VERSION 5.7 ;
  NOWIREEXTENSIONATPIN ON ;
  DIVIDERCHAR "/" ;
  BUSBITCHARS "[]" ;
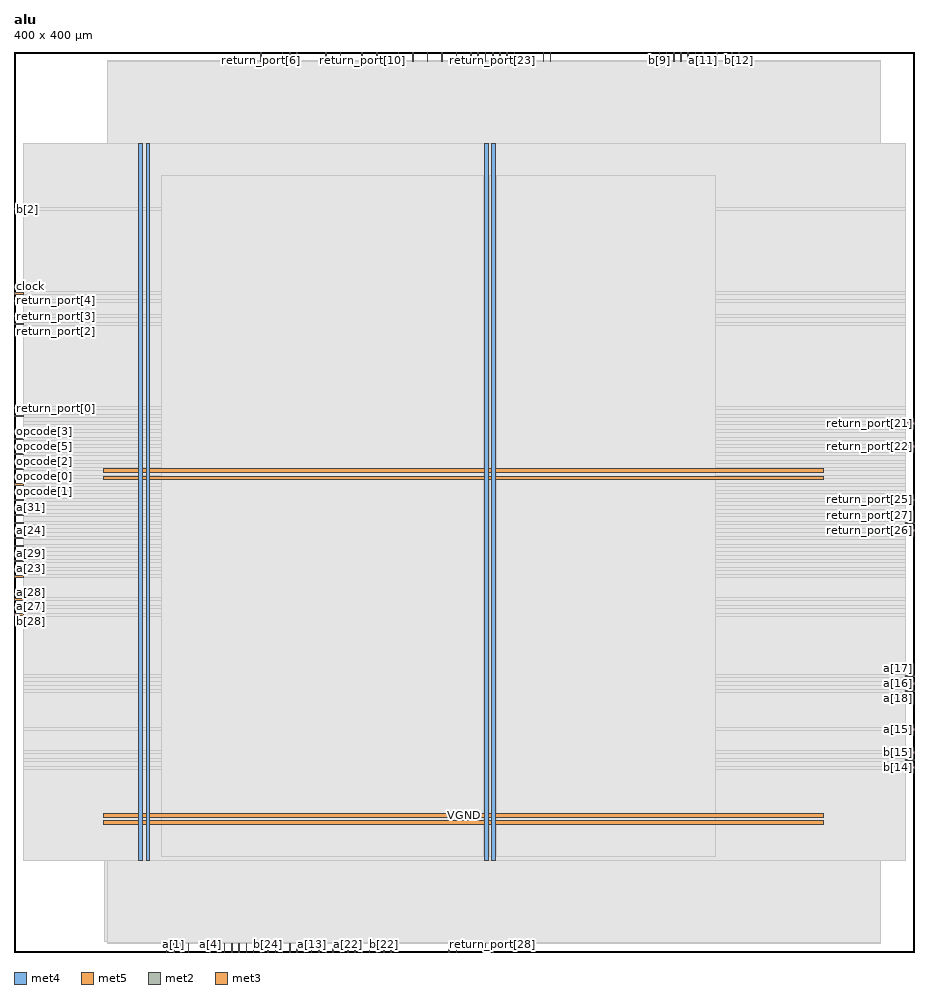
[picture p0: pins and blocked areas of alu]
MACRO alu
  CLASS BLOCK ;
  FOREIGN alu ;
  ORIGIN 0.000 0.000 ;
  SIZE 400.000 BY 400.000 ;
  PIN VGND
    DIRECTION INOUT ;
    USE GROUND ;
    PORT
      LAYER met4 ;
        RECT 58.840 40.560 60.440 359.280 ;
    END
    PORT
      LAYER met4 ;
        RECT 212.440 40.560 214.040 359.280 ;
    END
    PORT
      LAYER met5 ;
        RECT 39.780 59.950 359.960 61.550 ;
    END
    PORT
      LAYER met5 ;
        RECT 39.780 213.130 359.960 214.730 ;
    END
  END VGND
  PIN VPWR
    DIRECTION INOUT ;
    USE POWER ;
    PORT
      LAYER met4 ;
        RECT 55.540 40.560 57.140 359.280 ;
    END
    PORT
      LAYER met4 ;
        RECT 209.140 40.560 210.740 359.280 ;
    END
    PORT
      LAYER met5 ;
        RECT 39.780 56.650 359.960 58.250 ;
    END
    PORT
      LAYER met5 ;
        RECT 39.780 209.830 359.960 211.430 ;
    END
  END VPWR
  PIN a[0]
    DIRECTION INPUT ;
    USE SIGNAL ;
    ANTENNAGATEAREA 0.213000 ;
    PORT
      LAYER met2 ;
        RECT 67.710 0.000 67.990 4.000 ;
    END
  END a[0]
  PIN a[10]
    DIRECTION INPUT ;
    USE SIGNAL ;
    ANTENNAGATEAREA 0.213000 ;
    PORT
      LAYER met2 ;
        RECT 119.230 0.000 119.510 4.000 ;
    END
  END a[10]
  PIN a[11]
    DIRECTION INPUT ;
    USE SIGNAL ;
    ANTENNAGATEAREA 0.213000 ;
    PORT
      LAYER met2 ;
        RECT 305.990 396.000 306.270 400.000 ;
    END
  END a[11]
  PIN a[12]
    DIRECTION INPUT ;
    USE SIGNAL ;
    ANTENNAGATEAREA 0.159000 ;
    PORT
      LAYER met2 ;
        RECT 128.890 0.000 129.170 4.000 ;
    END
  END a[12]
  PIN a[13]
    DIRECTION INPUT ;
    USE SIGNAL ;
    ANTENNAGATEAREA 0.159000 ;
    PORT
      LAYER met2 ;
        RECT 132.110 0.000 132.390 4.000 ;
    END
  END a[13]
  PIN a[14]
    DIRECTION INPUT ;
    USE SIGNAL ;
    ANTENNAGATEAREA 0.213000 ;
    PORT
      LAYER met2 ;
        RECT 135.330 0.000 135.610 4.000 ;
    END
  END a[14]
  PIN a[15]
    DIRECTION INPUT ;
    USE SIGNAL ;
    ANTENNAGATEAREA 0.196500 ;
    PORT
      LAYER met3 ;
        RECT 396.000 98.640 400.000 99.240 ;
    END
  END a[15]
  PIN a[16]
    DIRECTION INPUT ;
    USE SIGNAL ;
    ANTENNAGATEAREA 0.196500 ;
    PORT
      LAYER met3 ;
        RECT 396.000 119.040 400.000 119.640 ;
    END
  END a[16]
  PIN a[17]
    DIRECTION INPUT ;
    USE SIGNAL ;
    ANTENNAGATEAREA 0.196500 ;
    PORT
      LAYER met3 ;
        RECT 396.000 122.440 400.000 123.040 ;
    END
  END a[17]
  PIN a[18]
    DIRECTION INPUT ;
    USE SIGNAL ;
    ANTENNAGATEAREA 0.196500 ;
    PORT
      LAYER met3 ;
        RECT 396.000 115.640 400.000 116.240 ;
    END
  END a[18]
  PIN a[19]
    DIRECTION INPUT ;
    USE SIGNAL ;
    ANTENNAGATEAREA 0.213000 ;
    PORT
      LAYER met2 ;
        RECT 141.770 0.000 142.050 4.000 ;
    END
  END a[19]
  PIN a[1]
    DIRECTION INPUT ;
    USE SIGNAL ;
    ANTENNAGATEAREA 0.196500 ;
    PORT
      LAYER met2 ;
        RECT 70.930 0.000 71.210 4.000 ;
    END
  END a[1]
  PIN a[20]
    DIRECTION INPUT ;
    USE SIGNAL ;
    ANTENNAGATEAREA 0.213000 ;
    PORT
      LAYER met2 ;
        RECT 138.550 0.000 138.830 4.000 ;
    END
  END a[20]
  PIN a[21]
    DIRECTION INPUT ;
    USE SIGNAL ;
    ANTENNAGATEAREA 0.196500 ;
    PORT
      LAYER met2 ;
        RECT 144.990 0.000 145.270 4.000 ;
    END
  END a[21]
  PIN a[22]
    DIRECTION INPUT ;
    USE SIGNAL ;
    ANTENNAGATEAREA 0.196500 ;
    PORT
      LAYER met2 ;
        RECT 148.210 0.000 148.490 4.000 ;
    END
  END a[22]
  PIN a[23]
    DIRECTION INPUT ;
    USE SIGNAL ;
    ANTENNAGATEAREA 0.213000 ;
    PORT
      LAYER met3 ;
        RECT 0.000 170.040 4.000 170.640 ;
    END
  END a[23]
  PIN a[24]
    DIRECTION INPUT ;
    USE SIGNAL ;
    ANTENNAGATEAREA 0.631200 ;
    ANTENNADIFFAREA 0.434700 ;
    PORT
      LAYER met3 ;
        RECT 0.000 187.040 4.000 187.640 ;
    END
  END a[24]
  PIN a[25]
    DIRECTION INPUT ;
    USE SIGNAL ;
    ANTENNAGATEAREA 0.196500 ;
    PORT
      LAYER met2 ;
        RECT 106.350 0.000 106.630 4.000 ;
    END
  END a[25]
  PIN a[26]
    DIRECTION INPUT ;
    USE SIGNAL ;
    ANTENNAGATEAREA 0.213000 ;
    PORT
      LAYER met3 ;
        RECT 0.000 166.640 4.000 167.240 ;
    END
  END a[26]
  PIN a[27]
    DIRECTION INPUT ;
    USE SIGNAL ;
    ANTENNAGATEAREA 0.560700 ;
    ANTENNADIFFAREA 0.434700 ;
    PORT
      LAYER met3 ;
        RECT 0.000 153.040 4.000 153.640 ;
    END
  END a[27]
  PIN a[28]
    DIRECTION INPUT ;
    USE SIGNAL ;
    ANTENNAGATEAREA 0.213000 ;
    PORT
      LAYER met3 ;
        RECT 0.000 156.440 4.000 157.040 ;
    END
  END a[28]
  PIN a[29]
    DIRECTION INPUT ;
    USE SIGNAL ;
    ANTENNAGATEAREA 0.593700 ;
    ANTENNADIFFAREA 0.434700 ;
    PORT
      LAYER met3 ;
        RECT 0.000 176.840 4.000 177.440 ;
    END
  END a[29]
  PIN a[2]
    DIRECTION INPUT ;
    USE SIGNAL ;
    ANTENNAGATEAREA 0.213000 ;
    PORT
      LAYER met2 ;
        RECT 74.150 0.000 74.430 4.000 ;
    END
  END a[2]
  PIN a[30]
    DIRECTION INPUT ;
    USE SIGNAL ;
    ANTENNAGATEAREA 0.247500 ;
    PORT
      LAYER met3 ;
        RECT 0.000 180.240 4.000 180.840 ;
    END
  END a[30]
  PIN a[31]
    DIRECTION INPUT ;
    USE SIGNAL ;
    ANTENNAGATEAREA 0.560700 ;
    ANTENNADIFFAREA 0.434700 ;
    PORT
      LAYER met3 ;
        RECT 0.000 197.240 4.000 197.840 ;
    END
  END a[31]
  PIN a[3]
    DIRECTION INPUT ;
    USE SIGNAL ;
    ANTENNAGATEAREA 0.247500 ;
    PORT
      LAYER met2 ;
        RECT 77.370 0.000 77.650 4.000 ;
    END
  END a[3]
  PIN a[4]
    DIRECTION INPUT ;
    USE SIGNAL ;
    ANTENNAGATEAREA 0.213000 ;
    PORT
      LAYER met2 ;
        RECT 87.030 0.000 87.310 4.000 ;
    END
  END a[4]
  PIN a[5]
    DIRECTION INPUT ;
    USE SIGNAL ;
    ANTENNAGATEAREA 0.213000 ;
    PORT
      LAYER met2 ;
        RECT 90.250 0.000 90.530 4.000 ;
    END
  END a[5]
  PIN a[6]
    DIRECTION INPUT ;
    USE SIGNAL ;
    ANTENNAGATEAREA 0.213000 ;
    PORT
      LAYER met2 ;
        RECT 93.470 0.000 93.750 4.000 ;
    END
  END a[6]
  PIN a[7]
    DIRECTION INPUT ;
    USE SIGNAL ;
    ANTENNAGATEAREA 0.196500 ;
    PORT
      LAYER met2 ;
        RECT 109.570 0.000 109.850 4.000 ;
    END
  END a[7]
  PIN a[8]
    DIRECTION INPUT ;
    USE SIGNAL ;
    ANTENNAGATEAREA 0.213000 ;
    PORT
      LAYER met2 ;
        RECT 116.010 0.000 116.290 4.000 ;
    END
  END a[8]
  PIN a[9]
    DIRECTION INPUT ;
    USE SIGNAL ;
    ANTENNAGATEAREA 0.196500 ;
    PORT
      LAYER met2 ;
        RECT 122.450 0.000 122.730 4.000 ;
    END
  END a[9]
  PIN b[0]
    DIRECTION INPUT ;
    USE SIGNAL ;
    ANTENNAGATEAREA 0.196500 ;
    PORT
      LAYER met2 ;
        RECT 238.370 396.000 238.650 400.000 ;
    END
  END b[0]
  PIN b[10]
    DIRECTION INPUT ;
    USE SIGNAL ;
    ANTENNAGATEAREA 0.126000 ;
    PORT
      LAYER met2 ;
        RECT 302.770 396.000 303.050 400.000 ;
    END
  END b[10]
  PIN b[11]
    DIRECTION INPUT ;
    USE SIGNAL ;
    ANTENNAGATEAREA 0.196500 ;
    PORT
      LAYER met2 ;
        RECT 312.430 396.000 312.710 400.000 ;
    END
  END b[11]
  PIN b[12]
    DIRECTION INPUT ;
    USE SIGNAL ;
    ANTENNAGATEAREA 0.213000 ;
    PORT
      LAYER met2 ;
        RECT 322.090 396.000 322.370 400.000 ;
    END
  END b[12]
  PIN b[13]
    DIRECTION INPUT ;
    USE SIGNAL ;
    ANTENNAGATEAREA 0.196500 ;
    PORT
      LAYER met2 ;
        RECT 318.870 396.000 319.150 400.000 ;
    END
  END b[13]
  PIN b[14]
    DIRECTION INPUT ;
    USE SIGNAL ;
    ANTENNAGATEAREA 0.196500 ;
    PORT
      LAYER met3 ;
        RECT 396.000 81.640 400.000 82.240 ;
    END
  END b[14]
  PIN b[15]
    DIRECTION INPUT ;
    USE SIGNAL ;
    ANTENNAGATEAREA 0.196500 ;
    PORT
      LAYER met3 ;
        RECT 396.000 85.040 400.000 85.640 ;
    END
  END b[15]
  PIN b[16]
    DIRECTION INPUT ;
    USE SIGNAL ;
    ANTENNAGATEAREA 0.213000 ;
    PORT
      LAYER met3 ;
        RECT 396.000 88.440 400.000 89.040 ;
    END
  END b[16]
  PIN b[17]
    DIRECTION INPUT ;
    USE SIGNAL ;
    ANTENNAGATEAREA 0.196500 ;
    PORT
      LAYER met2 ;
        RECT 151.430 0.000 151.710 4.000 ;
    END
  END b[17]
  PIN b[18]
    DIRECTION INPUT ;
    USE SIGNAL ;
    ANTENNAGATEAREA 0.159000 ;
    PORT
      LAYER met2 ;
        RECT 154.650 0.000 154.930 4.000 ;
    END
  END b[18]
  PIN b[19]
    DIRECTION INPUT ;
    USE SIGNAL ;
    ANTENNAGATEAREA 0.196500 ;
    PORT
      LAYER met2 ;
        RECT 157.870 0.000 158.150 4.000 ;
    END
  END b[19]
  PIN b[1]
    DIRECTION INPUT ;
    USE SIGNAL ;
    ANTENNAGATEAREA 0.159000 ;
    PORT
      LAYER met2 ;
        RECT 235.150 396.000 235.430 400.000 ;
    END
  END b[1]
  PIN b[20]
    DIRECTION INPUT ;
    USE SIGNAL ;
    ANTENNAGATEAREA 0.196500 ;
    PORT
      LAYER met2 ;
        RECT 125.670 0.000 125.950 4.000 ;
    END
  END b[20]
  PIN b[21]
    DIRECTION INPUT ;
    USE SIGNAL ;
    ANTENNAGATEAREA 0.196500 ;
    PORT
      LAYER met2 ;
        RECT 161.090 0.000 161.370 4.000 ;
    END
  END b[21]
  PIN b[22]
    DIRECTION INPUT ;
    USE SIGNAL ;
    ANTENNAGATEAREA 0.196500 ;
    PORT
      LAYER met2 ;
        RECT 164.310 0.000 164.590 4.000 ;
    END
  END b[22]
  PIN b[23]
    DIRECTION INPUT ;
    USE SIGNAL ;
    ANTENNAGATEAREA 0.196500 ;
    PORT
      LAYER met2 ;
        RECT 103.130 0.000 103.410 4.000 ;
    END
  END b[23]
  PIN b[24]
    DIRECTION INPUT ;
    USE SIGNAL ;
    ANTENNAGATEAREA 0.196500 ;
    PORT
      LAYER met2 ;
        RECT 112.790 0.000 113.070 4.000 ;
    END
  END b[24]
  PIN b[25]
    DIRECTION INPUT ;
    USE SIGNAL ;
    ANTENNAGATEAREA 0.196500 ;
    PORT
      LAYER met2 ;
        RECT 167.530 0.000 167.810 4.000 ;
    END
  END b[25]
  PIN b[26]
    DIRECTION INPUT ;
    USE SIGNAL ;
    ANTENNAGATEAREA 0.196500 ;
    PORT
      LAYER met2 ;
        RECT 96.690 0.000 96.970 4.000 ;
    END
  END b[26]
  PIN b[27]
    DIRECTION INPUT ;
    USE SIGNAL ;
    ANTENNAGATEAREA 0.213000 ;
    PORT
      LAYER met2 ;
        RECT 99.910 0.000 100.190 4.000 ;
    END
  END b[27]
  PIN b[28]
    DIRECTION INPUT ;
    USE SIGNAL ;
    ANTENNAGATEAREA 0.213000 ;
    PORT
      LAYER met3 ;
        RECT 0.000 149.640 4.000 150.240 ;
    END
  END b[28]
  PIN b[29]
    DIRECTION INPUT ;
    USE SIGNAL ;
    ANTENNAGATEAREA 0.593700 ;
    ANTENNADIFFAREA 0.434700 ;
    PORT
      LAYER met3 ;
        RECT 0.000 173.440 4.000 174.040 ;
    END
  END b[29]
  PIN b[2]
    DIRECTION INPUT ;
    USE SIGNAL ;
    ANTENNAGATEAREA 0.213000 ;
    PORT
      LAYER met3 ;
        RECT 0.000 329.840 4.000 330.440 ;
    END
  END b[2]
  PIN b[30]
    DIRECTION INPUT ;
    USE SIGNAL ;
    ANTENNAGATEAREA 0.213000 ;
    PORT
      LAYER met3 ;
        RECT 0.000 183.640 4.000 184.240 ;
    END
  END b[30]
  PIN b[31]
    DIRECTION INPUT ;
    USE SIGNAL ;
    ANTENNAGATEAREA 0.631200 ;
    ANTENNADIFFAREA 0.434700 ;
    PORT
      LAYER met3 ;
        RECT 0.000 190.440 4.000 191.040 ;
    END
  END b[31]
  PIN b[3]
    DIRECTION INPUT ;
    USE SIGNAL ;
    ANTENNAGATEAREA 0.196500 ;
    PORT
      LAYER met2 ;
        RECT 222.270 396.000 222.550 400.000 ;
    END
  END b[3]
  PIN b[4]
    DIRECTION INPUT ;
    USE SIGNAL ;
    ANTENNAGATEAREA 0.196500 ;
    PORT
      LAYER met2 ;
        RECT 219.050 396.000 219.330 400.000 ;
    END
  END b[4]
  PIN b[5]
    DIRECTION INPUT ;
    USE SIGNAL ;
    ANTENNAGATEAREA 0.213000 ;
    PORT
      LAYER met2 ;
        RECT 299.550 396.000 299.830 400.000 ;
    END
  END b[5]
  PIN b[6]
    DIRECTION INPUT ;
    USE SIGNAL ;
    ANTENNAGATEAREA 0.159000 ;
    PORT
      LAYER met2 ;
        RECT 296.330 396.000 296.610 400.000 ;
    END
  END b[6]
  PIN b[7]
    DIRECTION INPUT ;
    USE SIGNAL ;
    ANTENNAGATEAREA 0.213000 ;
    PORT
      LAYER met2 ;
        RECT 293.110 396.000 293.390 400.000 ;
    END
  END b[7]
  PIN b[8]
    DIRECTION INPUT ;
    USE SIGNAL ;
    ANTENNAGATEAREA 0.196500 ;
    PORT
      LAYER met2 ;
        RECT 289.890 396.000 290.170 400.000 ;
    END
  END b[8]
  PIN b[9]
    DIRECTION INPUT ;
    USE SIGNAL ;
    ANTENNAGATEAREA 0.126000 ;
    PORT
      LAYER met2 ;
        RECT 286.670 396.000 286.950 400.000 ;
    END
  END b[9]
  PIN clock
    DIRECTION INPUT ;
    USE SIGNAL ;
    ANTENNAGATEAREA 0.196500 ;
    PORT
      LAYER met3 ;
        RECT 0.000 292.440 4.000 293.040 ;
    END
  END clock
  PIN done_port
    DIRECTION OUTPUT ;
    USE SIGNAL ;
    ANTENNADIFFAREA 0.795200 ;
    PORT
      LAYER met3 ;
        RECT 0.000 193.840 4.000 194.440 ;
    END
  END done_port
  PIN opcode[0]
    DIRECTION INPUT ;
    USE SIGNAL ;
    ANTENNAGATEAREA 0.196500 ;
    PORT
      LAYER met3 ;
        RECT 0.000 210.840 4.000 211.440 ;
    END
  END opcode[0]
  PIN opcode[1]
    DIRECTION INPUT ;
    USE SIGNAL ;
    ANTENNAGATEAREA 0.213000 ;
    PORT
      LAYER met3 ;
        RECT 0.000 207.440 4.000 208.040 ;
    END
  END opcode[1]
  PIN opcode[2]
    DIRECTION INPUT ;
    USE SIGNAL ;
    ANTENNAGATEAREA 0.631200 ;
    ANTENNADIFFAREA 0.434700 ;
    PORT
      LAYER met3 ;
        RECT 0.000 214.240 4.000 214.840 ;
    END
  END opcode[2]
  PIN opcode[3]
    DIRECTION INPUT ;
    USE SIGNAL ;
    ANTENNAGATEAREA 0.196500 ;
    PORT
      LAYER met3 ;
        RECT 0.000 231.240 4.000 231.840 ;
    END
  END opcode[3]
  PIN opcode[4]
    DIRECTION INPUT ;
    USE SIGNAL ;
    ANTENNAGATEAREA 0.196500 ;
    PORT
      LAYER met3 ;
        RECT 0.000 217.640 4.000 218.240 ;
    END
  END opcode[4]
  PIN opcode[5]
    DIRECTION INPUT ;
    USE SIGNAL ;
    ANTENNAGATEAREA 0.196500 ;
    PORT
      LAYER met3 ;
        RECT 0.000 224.440 4.000 225.040 ;
    END
  END opcode[5]
  PIN opcode[6]
    DIRECTION INPUT ;
    USE SIGNAL ;
    ANTENNAGATEAREA 0.631200 ;
    ANTENNADIFFAREA 0.434700 ;
    PORT
      LAYER met3 ;
        RECT 0.000 227.840 4.000 228.440 ;
    END
  END opcode[6]
  PIN opcode[7]
    DIRECTION INPUT ;
    USE SIGNAL ;
    ANTENNAGATEAREA 0.631200 ;
    ANTENNADIFFAREA 0.434700 ;
    PORT
      LAYER met3 ;
        RECT 0.000 221.040 4.000 221.640 ;
    END
  END opcode[7]
  PIN reset
    DIRECTION INPUT ;
    USE SIGNAL ;
    ANTENNAGATEAREA 0.631200 ;
    ANTENNADIFFAREA 0.434700 ;
    PORT
      LAYER met3 ;
        RECT 0.000 204.040 4.000 204.640 ;
    END
  END reset
  PIN return_port[0]
    DIRECTION OUTPUT ;
    USE SIGNAL ;
    ANTENNADIFFAREA 0.795200 ;
    PORT
      LAYER met3 ;
        RECT 0.000 241.440 4.000 242.040 ;
    END
  END return_port[0]
  PIN return_port[10]
    DIRECTION OUTPUT ;
    USE SIGNAL ;
    ANTENNADIFFAREA 0.795200 ;
    PORT
      LAYER met2 ;
        RECT 154.650 396.000 154.930 400.000 ;
    END
  END return_port[10]
  PIN return_port[11]
    DIRECTION OUTPUT ;
    USE SIGNAL ;
    ANTENNADIFFAREA 0.795200 ;
    PORT
      LAYER met2 ;
        RECT 138.550 396.000 138.830 400.000 ;
    END
  END return_port[11]
  PIN return_port[12]
    DIRECTION OUTPUT ;
    USE SIGNAL ;
    ANTENNADIFFAREA 0.795200 ;
    PORT
      LAYER met2 ;
        RECT 170.750 396.000 171.030 400.000 ;
    END
  END return_port[12]
  PIN return_port[13]
    DIRECTION OUTPUT ;
    USE SIGNAL ;
    ANTENNADIFFAREA 0.795200 ;
    PORT
      LAYER met2 ;
        RECT 161.090 396.000 161.370 400.000 ;
    END
  END return_port[13]
  PIN return_port[14]
    DIRECTION OUTPUT ;
    USE SIGNAL ;
    ANTENNADIFFAREA 0.795200 ;
    PORT
      LAYER met2 ;
        RECT 183.630 396.000 183.910 400.000 ;
    END
  END return_port[14]
  PIN return_port[15]
    DIRECTION OUTPUT ;
    USE SIGNAL ;
    ANTENNADIFFAREA 0.795200 ;
    PORT
      LAYER met2 ;
        RECT 177.190 396.000 177.470 400.000 ;
    END
  END return_port[15]
  PIN return_port[16]
    DIRECTION OUTPUT ;
    USE SIGNAL ;
    ANTENNADIFFAREA 0.795200 ;
    PORT
      LAYER met2 ;
        RECT 196.510 396.000 196.790 400.000 ;
    END
  END return_port[16]
  PIN return_port[17]
    DIRECTION OUTPUT ;
    USE SIGNAL ;
    ANTENNADIFFAREA 0.795200 ;
    PORT
      LAYER met2 ;
        RECT 190.070 396.000 190.350 400.000 ;
    END
  END return_port[17]
  PIN return_port[18]
    DIRECTION OUTPUT ;
    USE SIGNAL ;
    ANTENNADIFFAREA 0.795200 ;
    PORT
      LAYER met2 ;
        RECT 202.950 396.000 203.230 400.000 ;
    END
  END return_port[18]
  PIN return_port[19]
    DIRECTION OUTPUT ;
    USE SIGNAL ;
    ANTENNADIFFAREA 0.795200 ;
    PORT
      LAYER met2 ;
        RECT 215.830 396.000 216.110 400.000 ;
    END
  END return_port[19]
  PIN return_port[1]
    DIRECTION OUTPUT ;
    USE SIGNAL ;
    ANTENNADIFFAREA 0.795200 ;
    PORT
      LAYER met3 ;
        RECT 0.000 238.040 4.000 238.640 ;
    END
  END return_port[1]
  PIN return_port[20]
    DIRECTION OUTPUT ;
    USE SIGNAL ;
    ANTENNADIFFAREA 0.795200 ;
    PORT
      LAYER met2 ;
        RECT 206.170 396.000 206.450 400.000 ;
    END
  END return_port[20]
  PIN return_port[21]
    DIRECTION OUTPUT ;
    USE SIGNAL ;
    ANTENNADIFFAREA 0.795200 ;
    PORT
      LAYER met3 ;
        RECT 396.000 234.640 400.000 235.240 ;
    END
  END return_port[21]
  PIN return_port[22]
    DIRECTION OUTPUT ;
    USE SIGNAL ;
    ANTENNADIFFAREA 0.795200 ;
    PORT
      LAYER met3 ;
        RECT 396.000 224.440 400.000 225.040 ;
    END
  END return_port[22]
  PIN return_port[23]
    DIRECTION OUTPUT ;
    USE SIGNAL ;
    ANTENNADIFFAREA 0.795200 ;
    PORT
      LAYER met2 ;
        RECT 212.610 396.000 212.890 400.000 ;
    END
  END return_port[23]
  PIN return_port[24]
    DIRECTION OUTPUT ;
    USE SIGNAL ;
    ANTENNADIFFAREA 0.795200 ;
    PORT
      LAYER met2 ;
        RECT 209.390 396.000 209.670 400.000 ;
    END
  END return_port[24]
  PIN return_port[25]
    DIRECTION OUTPUT ;
    USE SIGNAL ;
    ANTENNADIFFAREA 0.795200 ;
    PORT
      LAYER met3 ;
        RECT 396.000 200.640 400.000 201.240 ;
    END
  END return_port[25]
  PIN return_port[26]
    DIRECTION OUTPUT ;
    USE SIGNAL ;
    ANTENNADIFFAREA 0.795200 ;
    PORT
      LAYER met3 ;
        RECT 396.000 187.040 400.000 187.640 ;
    END
  END return_port[26]
  PIN return_port[27]
    DIRECTION OUTPUT ;
    USE SIGNAL ;
    ANTENNADIFFAREA 0.795200 ;
    PORT
      LAYER met3 ;
        RECT 396.000 190.440 400.000 191.040 ;
    END
  END return_port[27]
  PIN return_port[28]
    DIRECTION OUTPUT ;
    USE SIGNAL ;
    ANTENNADIFFAREA 0.795200 ;
    PORT
      LAYER met2 ;
        RECT 212.610 0.000 212.890 4.000 ;
    END
  END return_port[28]
  PIN return_port[29]
    DIRECTION OUTPUT ;
    USE SIGNAL ;
    ANTENNADIFFAREA 0.795200 ;
    PORT
      LAYER met2 ;
        RECT 209.390 0.000 209.670 4.000 ;
    END
  END return_port[29]
  PIN return_port[2]
    DIRECTION OUTPUT ;
    USE SIGNAL ;
    ANTENNADIFFAREA 0.795200 ;
    PORT
      LAYER met3 ;
        RECT 0.000 278.840 4.000 279.440 ;
    END
  END return_port[2]
  PIN return_port[30]
    DIRECTION OUTPUT ;
    USE SIGNAL ;
    ANTENNADIFFAREA 0.795200 ;
    PORT
      LAYER met2 ;
        RECT 196.510 0.000 196.790 4.000 ;
    END
  END return_port[30]
  PIN return_port[31]
    DIRECTION OUTPUT ;
    USE SIGNAL ;
    ANTENNADIFFAREA 0.795200 ;
    PORT
      LAYER met2 ;
        RECT 193.290 0.000 193.570 4.000 ;
    END
  END return_port[31]
  PIN return_port[3]
    DIRECTION OUTPUT ;
    USE SIGNAL ;
    ANTENNADIFFAREA 0.795200 ;
    PORT
      LAYER met3 ;
        RECT 0.000 282.240 4.000 282.840 ;
    END
  END return_port[3]
  PIN return_port[4]
    DIRECTION OUTPUT ;
    USE SIGNAL ;
    ANTENNADIFFAREA 0.795200 ;
    PORT
      LAYER met3 ;
        RECT 0.000 289.040 4.000 289.640 ;
    END
  END return_port[4]
  PIN return_port[5]
    DIRECTION OUTPUT ;
    USE SIGNAL ;
    ANTENNADIFFAREA 0.795200 ;
    PORT
      LAYER met2 ;
        RECT 122.450 396.000 122.730 400.000 ;
    END
  END return_port[5]
  PIN return_port[6]
    DIRECTION OUTPUT ;
    USE SIGNAL ;
    ANTENNADIFFAREA 0.795200 ;
    PORT
      LAYER met2 ;
        RECT 109.570 396.000 109.850 400.000 ;
    END
  END return_port[6]
  PIN return_port[7]
    DIRECTION OUTPUT ;
    USE SIGNAL ;
    ANTENNADIFFAREA 0.795200 ;
    PORT
      LAYER met2 ;
        RECT 119.230 396.000 119.510 400.000 ;
    END
  END return_port[7]
  PIN return_port[8]
    DIRECTION OUTPUT ;
    USE SIGNAL ;
    ANTENNADIFFAREA 0.795200 ;
    PORT
      LAYER met2 ;
        RECT 125.670 396.000 125.950 400.000 ;
    END
  END return_port[8]
  PIN return_port[9]
    DIRECTION OUTPUT ;
    USE SIGNAL ;
    ANTENNADIFFAREA 0.795200 ;
    PORT
      LAYER met2 ;
        RECT 144.990 396.000 145.270 400.000 ;
    END
  END return_port[9]
  PIN start_port
    DIRECTION INPUT ;
    USE SIGNAL ;
    ANTENNAGATEAREA 0.631200 ;
    ANTENNADIFFAREA 0.434700 ;
    PORT
      LAYER met3 ;
        RECT 0.000 200.640 4.000 201.240 ;
    END
  END start_port
  OBS
      LAYER nwell ;
        RECT 39.830 40.715 359.910 359.230 ;
      LAYER li1 ;
        RECT 40.020 40.715 359.720 359.125 ;
      LAYER met1 ;
        RECT 40.020 4.800 384.950 359.280 ;
      LAYER met2 ;
        RECT 41.490 395.720 109.290 396.170 ;
        RECT 110.130 395.720 118.950 396.170 ;
        RECT 119.790 395.720 122.170 396.170 ;
        RECT 123.010 395.720 125.390 396.170 ;
        RECT 126.230 395.720 138.270 396.170 ;
        RECT 139.110 395.720 144.710 396.170 ;
        RECT 145.550 395.720 154.370 396.170 ;
        RECT 155.210 395.720 160.810 396.170 ;
        RECT 161.650 395.720 170.470 396.170 ;
        RECT 171.310 395.720 176.910 396.170 ;
        RECT 177.750 395.720 183.350 396.170 ;
        RECT 184.190 395.720 189.790 396.170 ;
        RECT 190.630 395.720 196.230 396.170 ;
        RECT 197.070 395.720 202.670 396.170 ;
        RECT 203.510 395.720 205.890 396.170 ;
        RECT 206.730 395.720 209.110 396.170 ;
        RECT 209.950 395.720 212.330 396.170 ;
        RECT 213.170 395.720 215.550 396.170 ;
        RECT 216.390 395.720 218.770 396.170 ;
        RECT 219.610 395.720 221.990 396.170 ;
        RECT 222.830 395.720 234.870 396.170 ;
        RECT 235.710 395.720 238.090 396.170 ;
        RECT 238.930 395.720 286.390 396.170 ;
        RECT 287.230 395.720 289.610 396.170 ;
        RECT 290.450 395.720 292.830 396.170 ;
        RECT 293.670 395.720 296.050 396.170 ;
        RECT 296.890 395.720 299.270 396.170 ;
        RECT 300.110 395.720 302.490 396.170 ;
        RECT 303.330 395.720 305.710 396.170 ;
        RECT 306.550 395.720 312.150 396.170 ;
        RECT 312.990 395.720 318.590 396.170 ;
        RECT 319.430 395.720 321.810 396.170 ;
        RECT 322.650 395.720 384.930 396.170 ;
        RECT 41.490 4.280 384.930 395.720 ;
        RECT 41.490 3.670 67.430 4.280 ;
        RECT 68.270 3.670 70.650 4.280 ;
        RECT 71.490 3.670 73.870 4.280 ;
        RECT 74.710 3.670 77.090 4.280 ;
        RECT 77.930 3.670 86.750 4.280 ;
        RECT 87.590 3.670 89.970 4.280 ;
        RECT 90.810 3.670 93.190 4.280 ;
        RECT 94.030 3.670 96.410 4.280 ;
        RECT 97.250 3.670 99.630 4.280 ;
        RECT 100.470 3.670 102.850 4.280 ;
        RECT 103.690 3.670 106.070 4.280 ;
        RECT 106.910 3.670 109.290 4.280 ;
        RECT 110.130 3.670 112.510 4.280 ;
        RECT 113.350 3.670 115.730 4.280 ;
        RECT 116.570 3.670 118.950 4.280 ;
        RECT 119.790 3.670 122.170 4.280 ;
        RECT 123.010 3.670 125.390 4.280 ;
        RECT 126.230 3.670 128.610 4.280 ;
        RECT 129.450 3.670 131.830 4.280 ;
        RECT 132.670 3.670 135.050 4.280 ;
        RECT 135.890 3.670 138.270 4.280 ;
        RECT 139.110 3.670 141.490 4.280 ;
        RECT 142.330 3.670 144.710 4.280 ;
        RECT 145.550 3.670 147.930 4.280 ;
        RECT 148.770 3.670 151.150 4.280 ;
        RECT 151.990 3.670 154.370 4.280 ;
        RECT 155.210 3.670 157.590 4.280 ;
        RECT 158.430 3.670 160.810 4.280 ;
        RECT 161.650 3.670 164.030 4.280 ;
        RECT 164.870 3.670 167.250 4.280 ;
        RECT 168.090 3.670 193.010 4.280 ;
        RECT 193.850 3.670 196.230 4.280 ;
        RECT 197.070 3.670 209.110 4.280 ;
        RECT 209.950 3.670 212.330 4.280 ;
        RECT 213.170 3.670 384.930 4.280 ;
      LAYER met3 ;
        RECT 4.000 330.840 396.000 359.205 ;
        RECT 4.400 329.440 396.000 330.840 ;
        RECT 4.000 293.440 396.000 329.440 ;
        RECT 4.400 292.040 396.000 293.440 ;
        RECT 4.000 290.040 396.000 292.040 ;
        RECT 4.400 288.640 396.000 290.040 ;
        RECT 4.000 283.240 396.000 288.640 ;
        RECT 4.400 281.840 396.000 283.240 ;
        RECT 4.000 279.840 396.000 281.840 ;
        RECT 4.400 278.440 396.000 279.840 ;
        RECT 4.000 242.440 396.000 278.440 ;
        RECT 4.400 241.040 396.000 242.440 ;
        RECT 4.000 239.040 396.000 241.040 ;
        RECT 4.400 237.640 396.000 239.040 ;
        RECT 4.000 235.640 396.000 237.640 ;
        RECT 4.000 234.240 395.600 235.640 ;
        RECT 4.000 232.240 396.000 234.240 ;
        RECT 4.400 230.840 396.000 232.240 ;
        RECT 4.000 228.840 396.000 230.840 ;
        RECT 4.400 227.440 396.000 228.840 ;
        RECT 4.000 225.440 396.000 227.440 ;
        RECT 4.400 224.040 395.600 225.440 ;
        RECT 4.000 222.040 396.000 224.040 ;
        RECT 4.400 220.640 396.000 222.040 ;
        RECT 4.000 218.640 396.000 220.640 ;
        RECT 4.400 217.240 396.000 218.640 ;
        RECT 4.000 215.240 396.000 217.240 ;
        RECT 4.400 213.840 396.000 215.240 ;
        RECT 4.000 211.840 396.000 213.840 ;
        RECT 4.400 210.440 396.000 211.840 ;
        RECT 4.000 208.440 396.000 210.440 ;
        RECT 4.400 207.040 396.000 208.440 ;
        RECT 4.000 205.040 396.000 207.040 ;
        RECT 4.400 203.640 396.000 205.040 ;
        RECT 4.000 201.640 396.000 203.640 ;
        RECT 4.400 200.240 395.600 201.640 ;
        RECT 4.000 198.240 396.000 200.240 ;
        RECT 4.400 196.840 396.000 198.240 ;
        RECT 4.000 194.840 396.000 196.840 ;
        RECT 4.400 193.440 396.000 194.840 ;
        RECT 4.000 191.440 396.000 193.440 ;
        RECT 4.400 190.040 395.600 191.440 ;
        RECT 4.000 188.040 396.000 190.040 ;
        RECT 4.400 186.640 395.600 188.040 ;
        RECT 4.000 184.640 396.000 186.640 ;
        RECT 4.400 183.240 396.000 184.640 ;
        RECT 4.000 181.240 396.000 183.240 ;
        RECT 4.400 179.840 396.000 181.240 ;
        RECT 4.000 177.840 396.000 179.840 ;
        RECT 4.400 176.440 396.000 177.840 ;
        RECT 4.000 174.440 396.000 176.440 ;
        RECT 4.400 173.040 396.000 174.440 ;
        RECT 4.000 171.040 396.000 173.040 ;
        RECT 4.400 169.640 396.000 171.040 ;
        RECT 4.000 167.640 396.000 169.640 ;
        RECT 4.400 166.240 396.000 167.640 ;
        RECT 4.000 157.440 396.000 166.240 ;
        RECT 4.400 156.040 396.000 157.440 ;
        RECT 4.000 154.040 396.000 156.040 ;
        RECT 4.400 152.640 396.000 154.040 ;
        RECT 4.000 150.640 396.000 152.640 ;
        RECT 4.400 149.240 396.000 150.640 ;
        RECT 4.000 123.440 396.000 149.240 ;
        RECT 4.000 122.040 395.600 123.440 ;
        RECT 4.000 120.040 396.000 122.040 ;
        RECT 4.000 118.640 395.600 120.040 ;
        RECT 4.000 116.640 396.000 118.640 ;
        RECT 4.000 115.240 395.600 116.640 ;
        RECT 4.000 99.640 396.000 115.240 ;
        RECT 4.000 98.240 395.600 99.640 ;
        RECT 4.000 89.440 396.000 98.240 ;
        RECT 4.000 88.040 395.600 89.440 ;
        RECT 4.000 86.040 396.000 88.040 ;
        RECT 4.000 84.640 395.600 86.040 ;
        RECT 4.000 82.640 396.000 84.640 ;
        RECT 4.000 81.240 395.600 82.640 ;
        RECT 4.000 40.635 396.000 81.240 ;
      LAYER met4 ;
        RECT 65.615 42.335 208.740 345.265 ;
        RECT 211.140 42.335 212.040 345.265 ;
        RECT 214.440 42.335 311.585 345.265 ;
  END
END alu
END LIBRARY

